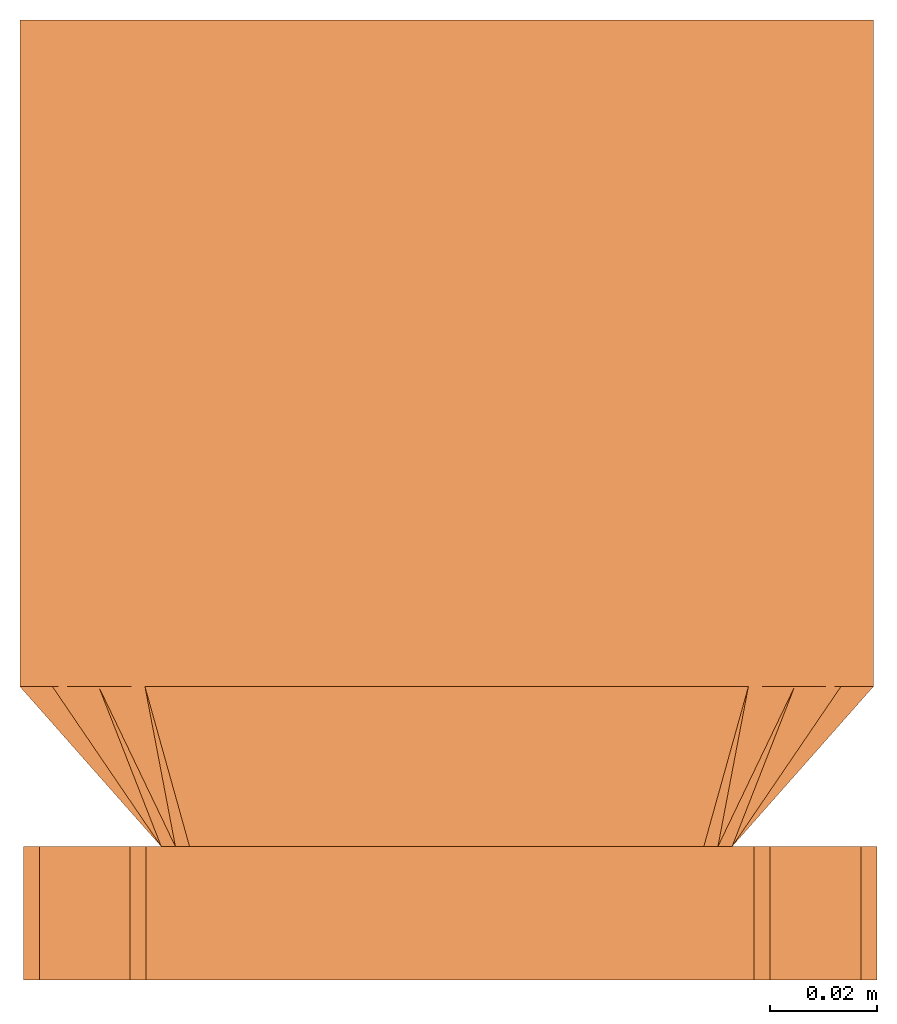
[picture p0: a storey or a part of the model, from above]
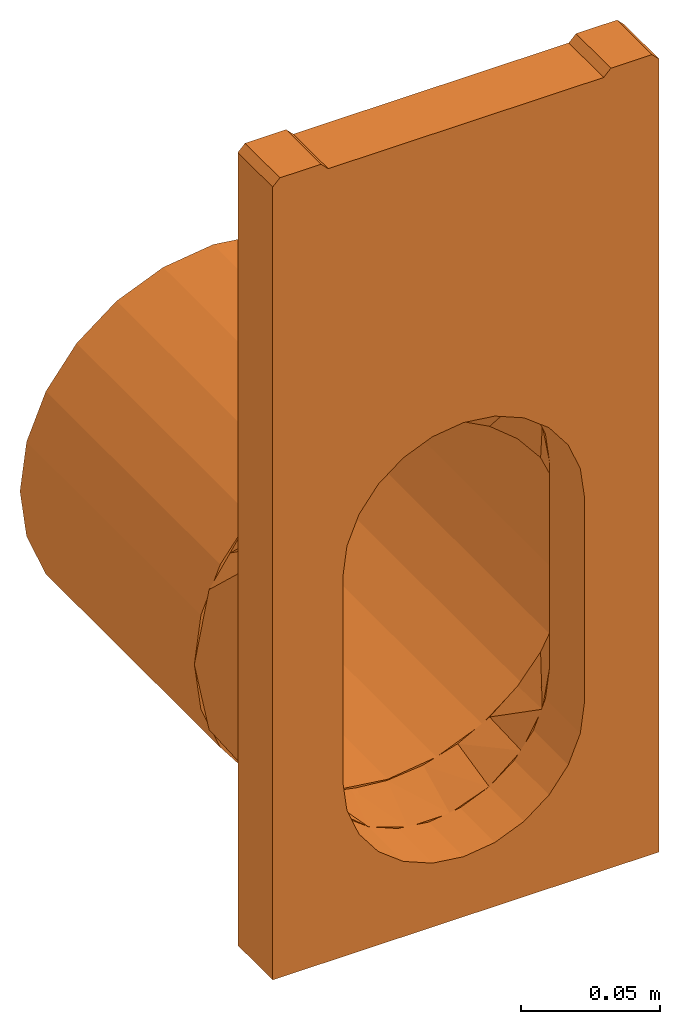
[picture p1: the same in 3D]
Properties of the parts of a building model (IFC2X3)

# File
Description: ViewDefinition [CoordinationView]
File name: 32308 - PD100 F 308 Inlet outlet endcap.ifc
Time: 2013-10-11T12:32:05
Written by: Autodesk Revit 2013
Made in: 20120221_2030(x64)

# IfcProject, Project Number
LongName: Project Name; Phase: Project Status

# IfcSite, Default
RefLatitude: 42, 21, 30, 344238; RefLongitude: -71, -3, -35, -194702; RefElevation: 0 mm

# IfcBuilding
Pset_BuildingCommon - NumberOfStoreys: 2
Other - Project Issue Date: Issue Date; Project Number: Project Number; Project Status: Project Status; Project Name: Project Name; Client Name: Owner; Project Address: Enter address here

# IfcBuildingStorey (2)
Constraints - Elevation Base: 0
Graphics - Symbol at End 2 Default: yes; Line Weight: 1; Symbol: M_Level Head - Circle: M_Level Head - Circle; Line Pattern: Center; Symbol at End 1 Default: no; Color: 0
Identity Data - Structural: no; Building Story: yes
Dimensions - Computation Height: 0 mm
Name | LongName = Name | Elevation (mm) = Constraints, Elevation (mm)
B.O. Footing | B.O. Footing | -4600
T.O. Footing | T.O. Footing | -4300

# IfcBuildingElementProxy: 32308 - PD100 F 308 Inlet/outlet endcap, Civil-Drainage-Channel-ACO-RoadDrain 100:32308 - PD100 F 308 Inlet/outlet endcap:32308 - PD100 F 308 Inlet/outlet endcap:310733
In: B.O. Footing
Material: Acetal Resin, Black
Other - CreatedBy: www.aco.co.uk; Revision: 1
Construction - Channel 160mm Wide: no; Grating 500mm: no; Access unit: no; 32900 - Sump Unit: no; Closing End Cap: no; Inlet Outlet end cap_350 high: yes; Inlet Outlet end cap_450 high: no
Constraints - Level: Level: T.O. Footing; Moves With Nearby Elements: no
Phasing - Phase Created: Phase 1
Dimensions - Straight Void Length: 25 mm; Length: 500 mm; Volume: 1130681 mm3; Custom Void Length: 0 mm; Total Depth: 250 mm; Straight Void Start: 0 mm; I/O End Cap Void: 128.041 mm; Invert Depth.: 175 mm; Void Depth: -350 mm
Pset_BuildingElementProxyCommon - Reference: 32308 - PD100 F 308 Inlet/outlet endcap
Data - Connection Pipe O.D: Ø160mm; Product Standard: N/A; Hydraulic Performance: N/A; ACO Hydraulic Design Software: N/A; Product Dimensions: 25mm x 160mm x 350mm (LxWxH); Concrete Surround Volume - Load Class F 900 - Concrete Pavement: N/A; Product Weight: 2.2 Kg; Invert Depth: N/A; Channel C.S.A: N/A; Installation - Concrete Grade: N/A; Load Class: N/A
Identity Data - Price: POA - contact ACO; Telephone: +44 (0)1462 816666; Product Page URL: http://www.aco.co.uk/product_detail.php?id=21; Model Description: Monolithic Channel drainage system; Assembly Description: Rain Water Drainage; Model: ACO RoadDrain 100 PD100F; URL: www.aco.co.uk; Address: ACO Business Park, Hitchin Road, Shefford, Bedfordshire, United Kingdom SG17 5TE; e-mail Technical: technical@aco.co.uk; Maintenance guidelines: http://www.aco.co.uk/download.php?id=256; Watermark 1: This file is the property of ACO Technologies PLC; Watermarked With: BIM Manager Premium Suite; Cost: 0; Product Code: 32308; Assembly Code: D2040; e-mail Sales: customersupport@aco.co.uk; Product brochure: http://www.aco.co.uk/download.php?id=256; Manufacturer: ACO Technologies plc - ACO Water Management Division; Type Comments: ACO RoadDrain PD100 F 308 Inlet/Outlet End Cap; Fax: +44 (0)1462 815895; OmniClass Title: Rainwater Removal; OmniClass Number: 23.70.50.24; Watermark 2: This file is water marked and users are prohibited to reproduce, adapt, distribute this information; Installation guidelines: http://www.aco.co.uk/download.php?id=256; Watermarked By: www.aco.co.uk
General - TagNumber: 0.000000; SerialNumber: 0.000000
Materials and Finishes - Access Cover/Frame Finish: N/A; End Cap Material: Vienite® Synthetic Resin Concrete; Grating Material: N/A; Channel Colour: N/A; End Cap Colour: Black; Grating Colour: N/A; Access Cover/Frame Material: N/A; Connection Pipe Material: MDPE; Channel Material: N/A; Grating Finish: N/A; Connection Pipe Colour: Black; Access Cover/Frame Colour: N/A
Green Building Properties - Access Cover/Frame Recycled Material Content: N/A; Grating Recycled Material Content: N/A; Channel Recyclable: N/A; Channel Recycled Material Content: N/A; End Cap Recyclable: Fully recyclable; Access Cover/Frame Recyclable: N/A; Grating Recyclable: N/A; End Cap Recycled Material Content: 20% minimum

# IfcOpeningElement: Recess
In: T.O. Footing
Structural - Structural: no; Enable Analytical Model: no
Dimensions - Thickness: 1550 mm; Perimeter: 22200 mm; Area: 30800000 mm2; Volume: 47734543200 mm3
Constraints - Level: Level: T.O. Footing; Height Offset From Level: 0 mm; Room Bounding: yes; Related to Mass: no
Phasing - Phase Created: Phase 1
Graphics - Coarse Scale Fill Color: 0
Analytical Properties - Roughness: 1; Heat Transfer Coefficient (U): 0.558; Thermal mass: 2039700; Absorptance: 0.1; Thermal Resistance (R): 1.79211
Construction - Function: 0; Default Thickness: 1550 mm
Materials and Finishes - Structural Material: Grass

# IfcSlab: Floor:Generic Floor - 400mm, Floor:Generic Floor - 400mm:136436
In: T.O. Footing
PredefinedType: FLOOR; Material: Grass 50 mm, Earth 1500 mm
Structural - Structural: no; Enable Analytical Model: no
Dimensions - Thickness: 1550 mm; Perimeter: 22200 mm; Area: 30800000 mm2; Volume: 47734543200 mm3
Constraints - Level: Level: T.O. Footing; Height Offset From Level: 0 mm; Room Bounding: yes; Related to Mass: no
Phasing - Phase Created: Phase 1
Pset_SlabCommon - Reference: Generic Floor - 400mm; IsExternal: no; LoadBearing: yes
Graphics - Coarse Scale Fill Color: 0
Analytical Properties - Roughness: 1; Heat Transfer Coefficient (U): 0.558; Thermal mass: 2039700; Absorptance: 0.1; Thermal Resistance (R): 1.79211
Construction - Function: 0; Default Thickness: 1550 mm
Materials and Finishes - Structural Material: Grass
